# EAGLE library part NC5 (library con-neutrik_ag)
Neutrik Audio Connector XLR SERIES Stereo 1/4" jack Source: www.neutrik.com/

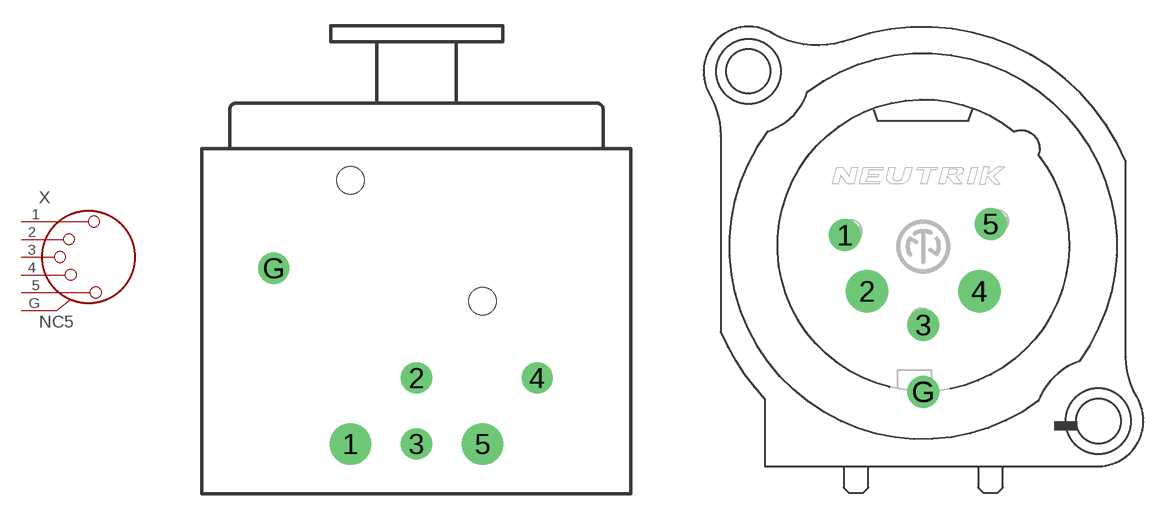
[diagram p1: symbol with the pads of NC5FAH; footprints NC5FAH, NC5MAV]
Designator prefix X

## NC5FAH  [NC5FAH]
1  1  pas
2  2  pas
3  3  pas
4  4  pas
5  5  pas
G  G  pas

## NC5MAV  [NC5MAV]
Pads as for NC5FAH

## NC5FBH  [NC5FBH]
Pads as for NC5FAH

## NC5FBH-B  [NC5FBH-B]
Pads as for NC5FAH

## NC5FBV  [NC5FBV]
Pads as for NC5FAH

## NC5FGV-B  [NC5FBV-B]
Pads as for NC5FAH

## NC5MAH  [NC5MAH]
Pads as for NC5FAH

## NC5MBH  [NC5MBH]
Pads as for NC5FAH

## NC5MBN-B  [NC5MBH-B]
Pads as for NC5FAH

## NC5MBV  [NC5MBV]
Pads as for NC5FAH

## NC5FAV  [NC5FAV]
Pads as for NC5FAH

## Footprint NC5FAH (pad centres in mm)
Neutrik Audio Connector Source: www.neutrik.com/... 210_142701.pdf
drill 1.6 round: 1 -3.81,-3.815; 5 3.81,-3.815
drill 1.2 round: 2 0,0; 3 0,-3.815; 4 6.98,0; G -8.25,6.355
hole 1.6 at 3.81,4.445
hole 1.6 at -3.81,11.43

## Footprint NC5MAV (pad centres in mm)
Neutrik Audio Connector Source: www.neutrik.com/... 210_257601.pdf
drill 1.2 round: 1 -4.445,0.635; 3 0,-4.445; 5 3.81,1.27; G 0,-8.225
drill 1.6 round: 2 -3.175,-2.54; 4 3.175,-2.54

## Footprint NC5FBH (pad centres in mm)
Neutrik Audio Connector Source: www.neutrik.com/... 210_2351.pdf
drill 1.6 round: 1 -3.81,-3.815; 5 3.81,-3.815
drill 1.2 round: 2 0,0; 3 0,-3.815; 4 6.98,0; G -8.25,6.355
hole 1.6 at 3.81,4.445
hole 1.6 at -3.81,11.43

## Footprint NC5FBH-B (pad centres in mm)
Neutrik Audio Connector Source: www.neutrik.com/... 210_1401.pdf
drill 1.6 round: 1 -3.81,-3.815; 5 3.81,-3.815
drill 1.2 round: 2 0,0; 3 0,-3.815; 4 6.98,0; G -8.25,6.355
hole 1.6 at 3.81,4.445
hole 1.6 at -3.81,11.43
